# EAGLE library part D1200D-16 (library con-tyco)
DYNAMIC D1200D 2.5mm PITCH HDR ASSY (V-TYPE) Source: Data sheet

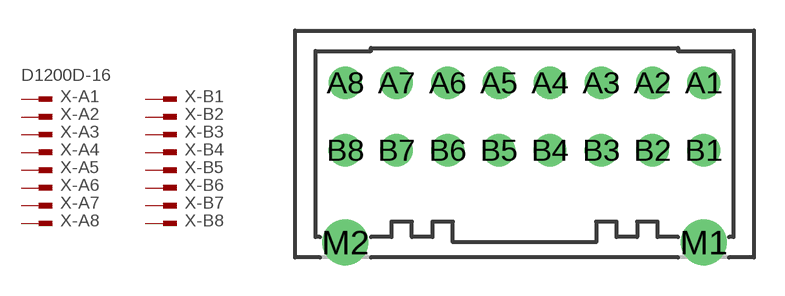
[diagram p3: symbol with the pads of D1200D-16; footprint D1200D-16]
Designator prefix X; gates -A1=PIN_V -A2=PIN -A3=PIN -A4=PIN -A5=PIN -A6=PIN -A7=PIN -A8=PIN -B1=PIN -B2=PIN -B3=PIN -B4=PIN -B5=PIN -B6=PIN -B7=PIN -B8=PIN

## D1200D-16  [D1200D-16]
A1  -A1:1  pas
A2  -A2:1  pas
A3  -A3:1  pas
A4  -A4:1  pas
A5  -A5:1  pas
A6  -A6:1  pas
A7  -A7:1  pas
A8  -A8:1  pas
B1  -B1:1  pas
B2  -B2:1  pas
B3  -B3:1  pas
B4  -B4:1  pas
B5  -B5:1  pas
B6  -B6:1  pas
B7  -B7:1  pas
B8  -B8:1  pas

## Footprint D1200D-16 (pad centres in mm)
DYNAMIC D1200D 2.5mm PITCH HDR ASSY (V-TYPE) Source: Data sheet
drill 0.8 pad 1.6: A1 8.75,3.3; A2 6.25,3.3; A3 3.75,3.3; A4 1.25,3.3; A5 -1.25,3.3; A6 -3.75,3.3; A7 -6.25,3.3; A8 -8.75,3.3; B1 8.75,0; B2 6.25,0; B3 3.75,0; B4 1.25,0; B5 -1.25,0; B6 -3.75,0; B7 -6.25,0; B8 -8.75,0
drill 1.5 pad 2: M1 8.75,-4.5; M2 -8.75,-4.5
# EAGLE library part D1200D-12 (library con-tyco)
DYNAMIC D1200D 2.5mm PITCH HDR ASSY (V-TYPE) Source: Data sheet

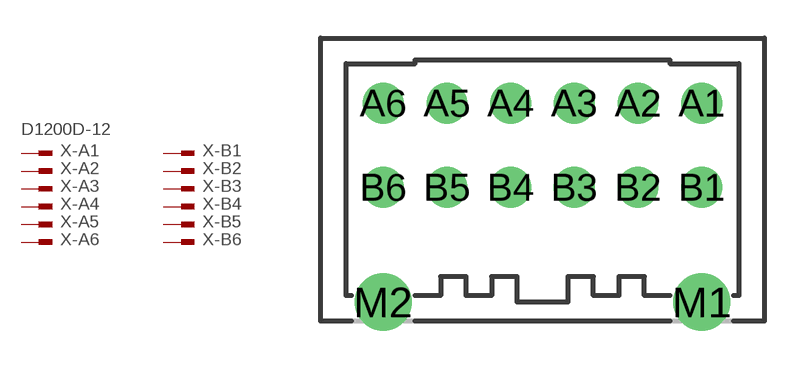
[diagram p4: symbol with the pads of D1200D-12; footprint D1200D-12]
Designator prefix X; gates -A1=PIN_V -A2=PIN -A3=PIN -A4=PIN -A5=PIN -A6=PIN -B1=PIN -B2=PIN -B3=PIN -B4=PIN -B5=PIN -B6=PIN

## D1200D-12  [D1200D-12]
A1  -A1:1  pas
A2  -A2:1  pas
A3  -A3:1  pas
A4  -A4:1  pas
A5  -A5:1  pas
A6  -A6:1  pas
B1  -B1:1  pas
B2  -B2:1  pas
B3  -B3:1  pas
B4  -B4:1  pas
B5  -B5:1  pas
B6  -B6:1  pas

## Footprint D1200D-12 (pad centres in mm)
DYNAMIC D1200D 2.5mm PITCH HDR ASSY (V-TYPE) Source: Data sheet
drill 0.8 pad 1.6: A1 6.25,3.3; A2 3.75,3.3; A3 1.25,3.3; A4 -1.25,3.3; A5 -3.75,3.3; A6 -6.25,3.3; B1 6.25,0; B2 3.75,0; B3 1.25,0; B4 -1.25,0; B5 -3.75,0; B6 -6.25,0
drill 1.5 pad 2: M1 6.25,-4.5; M2 -6.25,-4.5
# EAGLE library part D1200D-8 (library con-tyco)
DYNAMIC D1200D 2.5mm PITCH HDR ASSY (V-TYPE) Source: Data sheet

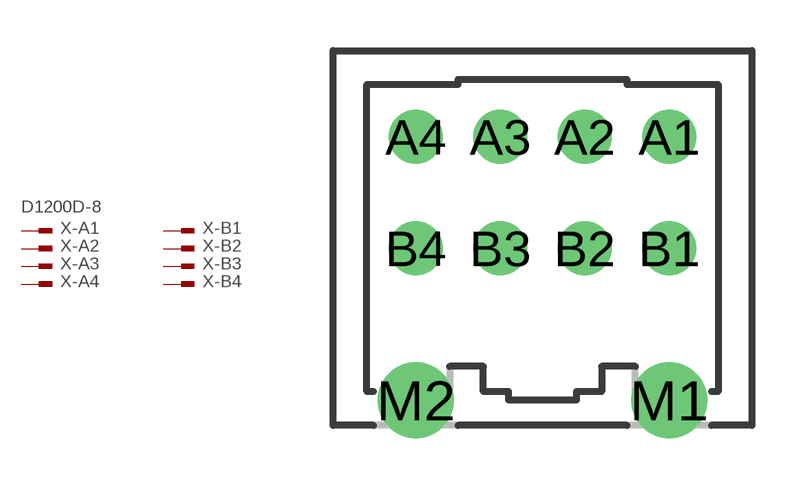
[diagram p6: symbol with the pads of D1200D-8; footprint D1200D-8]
Designator prefix X; gates -A1=PIN_V -A2=PIN -A3=PIN -A4=PIN -B1=PIN -B2=PIN -B3=PIN -B4=PIN

## D1200D-8  [D1200D-8]
A1  -A1:1  pas
A2  -A2:1  pas
A3  -A3:1  pas
A4  -A4:1  pas
B1  -B1:1  pas
B2  -B2:1  pas
B3  -B3:1  pas
B4  -B4:1  pas

## Footprint D1200D-8 (pad centres in mm)
DYNAMIC D1200D 2.5mm PITCH HDR ASSY (V-TYPE) Source: Data sheet
drill 0.8 pad 1.6: A1 3.75,3.3; A2 1.25,3.3; A3 -1.25,3.3; A4 -3.75,3.3; B1 3.75,0; B2 1.25,0; B3 -1.25,0; B4 -3.75,0
drill 1.5 pad 2: M1 3.75,-4.5; M2 -3.75,-4.5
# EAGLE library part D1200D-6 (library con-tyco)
DYNAMIC D1200D 2.5mm PITCH HDR ASSY (V-TYPE) Source: Data sheet

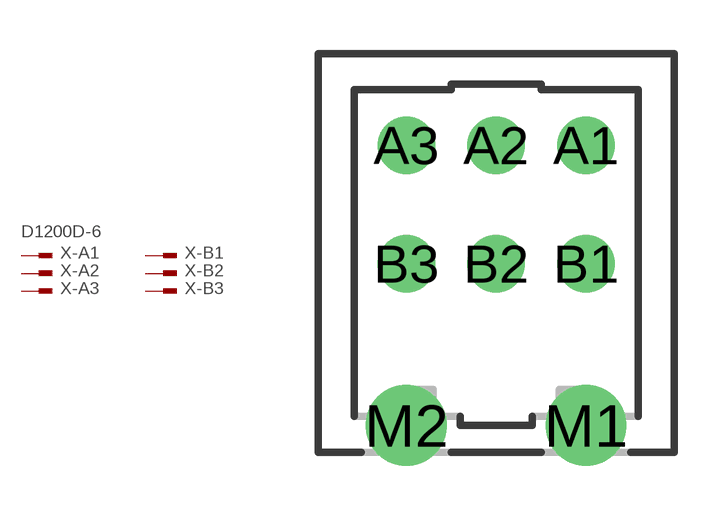
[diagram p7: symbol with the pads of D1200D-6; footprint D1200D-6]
Designator prefix X; gates -A1=PIN_V -A2=PIN -A3=PIN -B1=PIN -B2=PIN -B3=PIN

## D1200D-6  [D1200D-6]
A1  -A1:1  pas
A2  -A2:1  pas
A3  -A3:1  pas
B1  -B1:1  pas
B2  -B2:1  pas
B3  -B3:1  pas

## Footprint D1200D-6 (pad centres in mm)
DYNAMIC D1200D 2.5mm PITCH HDR ASSY (V-TYPE) Source: Data sheet
drill 0.8 pad 1.6: A1 2.5,3.3; A2 0,3.3; A3 -2.5,3.3; B1 2.5,0; B2 0,0; B3 -2.5,0
drill 1.5 pad 2: M1 2.5,-4.5; M2 -2.5,-4.5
